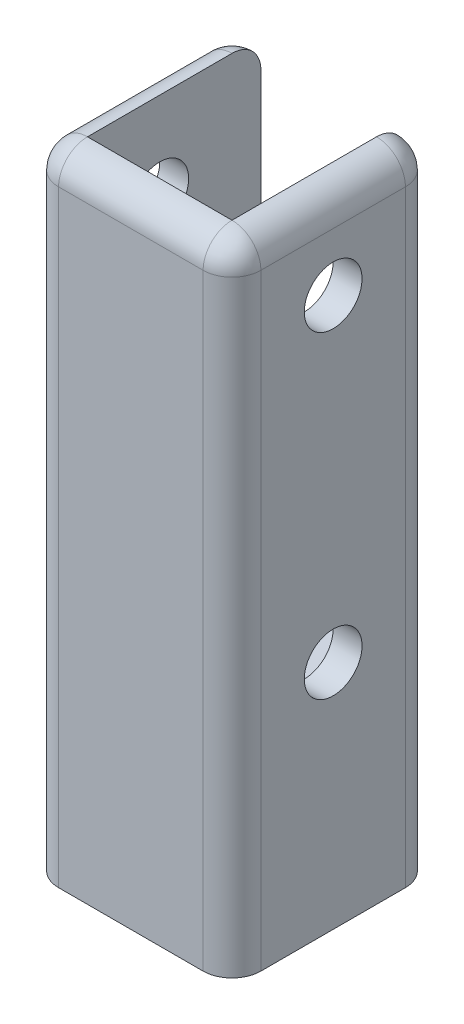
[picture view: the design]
ISO-10303-21;
HEADER;
FILE_DESCRIPTION(('STEP AP214'),'2;1');
FILE_NAME('part.step','',(''),(''),'','','');
FILE_SCHEMA(('AUTOMOTIVE_DESIGN { 1 0 10303 214 1 1 1 1 }'));
ENDSEC;
DATA;
#1=APPLICATION_CONTEXT('core data for automotive mechanical design processes');
#2=APPLICATION_PROTOCOL_DEFINITION('international standard','automotive_design',2000,#1);
#3=PRODUCT_CONTEXT('',#1,'mechanical');
#4=PRODUCT('Part','Part','',(#3));
#5=PRODUCT_RELATED_PRODUCT_CATEGORY('part','',(#4));
#6=PRODUCT_DEFINITION_FORMATION('','',#4);
#7=PRODUCT_DEFINITION_CONTEXT('part definition',#1,'design');
#8=PRODUCT_DEFINITION('design','',#6,#7);
#9=PRODUCT_DEFINITION_SHAPE('','',#8);
#10=(LENGTH_UNIT() NAMED_UNIT(*) SI_UNIT(.MILLI.,.METRE.));
#11=(NAMED_UNIT(*) PLANE_ANGLE_UNIT() SI_UNIT($,.RADIAN.));
#12=(NAMED_UNIT(*) SI_UNIT($,.STERADIAN.) SOLID_ANGLE_UNIT());
#13=UNCERTAINTY_MEASURE_WITH_UNIT(LENGTH_MEASURE(1.E-05),#10,'distance_accuracy_value','');
#14=(GEOMETRIC_REPRESENTATION_CONTEXT(3) GLOBAL_UNCERTAINTY_ASSIGNED_CONTEXT((#13)) GLOBAL_UNIT_ASSIGNED_CONTEXT((#10,
#11,#12)) REPRESENTATION_CONTEXT('',''));
#15=CARTESIAN_POINT('',(0.,0.,0.));
#16=DIRECTION('',(0.,0.,1.));
#17=DIRECTION('',(1.,0.,0.));
#18=AXIS2_PLACEMENT_3D('',#15,#16,#17);
#19=CARTESIAN_POINT('',(0.,55.,0.));
#20=DIRECTION('',(0.,1.,0.));
#21=DIRECTION('',(0.,0.,1.));
#22=AXIS2_PLACEMENT_3D('',#19,#20,#21);
#23=PLANE('',#22);
#24=DIRECTION('',(1.,0.,0.));
#25=VECTOR('',#24,1.);
#26=CARTESIAN_POINT('',(0.,55.,25.));
#27=LINE('',#26,#25);
#28=CARTESIAN_POINT('',(-25.,55.,25.0000000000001));
#29=VERTEX_POINT('',#28);
#30=CARTESIAN_POINT('',(25.,55.,25.));
#31=VERTEX_POINT('',#30);
#32=EDGE_CURVE('E278',#29,#31,#27,.T.);
#33=ORIENTED_EDGE('',*,*,#32,.T.);
#34=DIRECTION('',(0.,0.,-1.));
#35=VECTOR('',#34,1.);
#36=CARTESIAN_POINT('',(25.,55.,0.));
#37=LINE('',#36,#35);
#38=CARTESIAN_POINT('',(25.,55.,-35.));
#39=VERTEX_POINT('',#38);
#40=EDGE_CURVE('E264',#31,#39,#37,.T.);
#41=ORIENTED_EDGE('',*,*,#40,.T.);
#42=DIRECTION('',(-1.,0.,0.));
#43=VECTOR('',#42,1.);
#44=CARTESIAN_POINT('',(0.,55.,-35.));
#45=LINE('',#44,#43);
#46=CARTESIAN_POINT('',(-25.,55.,-35.));
#47=VERTEX_POINT('',#46);
#48=EDGE_CURVE('E266',#39,#47,#45,.T.);
#49=ORIENTED_EDGE('',*,*,#48,.T.);
#50=DIRECTION('',(0.,0.,1.));
#51=VECTOR('',#50,1.);
#52=CARTESIAN_POINT('',(-25.,55.,0.));
#53=LINE('',#52,#51);
#54=EDGE_CURVE('E259',#47,#29,#53,.T.);
#55=ORIENTED_EDGE('',*,*,#54,.T.);
#56=EDGE_LOOP('',(#33,#41,#49,#55));
#57=FACE_BOUND('',#56,.T.);
#58=ADVANCED_FACE('F41',(#57),#23,.T.);
#59=CARTESIAN_POINT('',(25.,0.,25.));
#60=DIRECTION('',(0.,1.,0.));
#61=DIRECTION('',(0.,0.,1.));
#62=AXIS2_PLACEMENT_3D('',#59,#60,#61);
#63=PLANE('',#62);
#64=CARTESIAN_POINT('',(-24.0588806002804,0.,-23.6603413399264));
#65=DIRECTION('',(0.,-1.,0.));
#66=DIRECTION('',(0.,0.,-1.));
#67=AXIS2_PLACEMENT_3D('',#64,#65,#66);
#68=CIRCLE('',#67,2.5);
#69=CARTESIAN_POINT('',(-24.0588806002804,0.,-26.1603413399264));
#70=VERTEX_POINT('',#69);
#71=EDGE_CURVE('E489',#70,#70,#68,.T.);
#72=ORIENTED_EDGE('',*,*,#71,.F.);
#73=EDGE_LOOP('',(#72));
#74=FACE_BOUND('',#73,.T.);
#75=CARTESIAN_POINT('',(22.9411193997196,0.,-23.6603413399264));
#76=DIRECTION('',(0.,-1.,0.));
#77=DIRECTION('',(0.,0.,-1.));
#78=AXIS2_PLACEMENT_3D('',#75,#76,#77);
#79=CIRCLE('',#78,2.5);
#80=CARTESIAN_POINT('',(22.9411193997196,0.,-26.1603413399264));
#81=VERTEX_POINT('',#80);
#82=EDGE_CURVE('E1132',#81,#81,#79,.T.);
#83=ORIENTED_EDGE('',*,*,#82,.F.);
#84=EDGE_LOOP('',(#83));
#85=FACE_BOUND('',#84,.T.);
#86=CARTESIAN_POINT('',(22.9411193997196,0.,23.3396586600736));
#87=DIRECTION('',(0.,-1.,0.));
#88=DIRECTION('',(0.,0.,-1.));
#89=AXIS2_PLACEMENT_3D('',#86,#87,#88);
#90=CIRCLE('',#89,2.5);
#91=CARTESIAN_POINT('',(22.9411193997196,0.,20.8396586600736));
#92=VERTEX_POINT('',#91);
#93=EDGE_CURVE('E506',#92,#92,#90,.T.);
#94=ORIENTED_EDGE('',*,*,#93,.F.);
#95=EDGE_LOOP('',(#94));
#96=FACE_BOUND('',#95,.T.);
#97=CARTESIAN_POINT('',(-24.0588806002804,0.,23.3396586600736));
#98=DIRECTION('',(0.,-1.,0.));
#99=DIRECTION('',(0.,0.,-1.));
#100=AXIS2_PLACEMENT_3D('',#97,#98,#99);
#101=CIRCLE('',#100,2.5);
#102=CARTESIAN_POINT('',(-24.0588806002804,0.,20.8396586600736));
#103=VERTEX_POINT('',#102);
#104=EDGE_CURVE('E503',#103,#103,#101,.T.);
#105=ORIENTED_EDGE('',*,*,#104,.F.);
#106=EDGE_LOOP('',(#105));
#107=FACE_BOUND('',#106,.T.);
#108=CARTESIAN_POINT('',(25.,0.,25.));
#109=DIRECTION('',(0.,1.,0.));
#110=DIRECTION('',(0.,0.,1.));
#111=AXIS2_PLACEMENT_3D('',#108,#109,#110);
#112=CIRCLE('',#111,10.);
#113=CARTESIAN_POINT('',(25.,0.,35.));
#114=VERTEX_POINT('',#113);
#115=CARTESIAN_POINT('',(35.,0.,25.));
#116=VERTEX_POINT('',#115);
#117=EDGE_CURVE('E420',#114,#116,#112,.T.);
#118=ORIENTED_EDGE('',*,*,#117,.F.);
#119=DIRECTION('',(1.,0.,0.));
#120=VECTOR('',#119,1.);
#121=CARTESIAN_POINT('',(-25.,0.,35.));
#122=LINE('',#121,#120);
#123=CARTESIAN_POINT('',(-25.,0.,35.));
#124=VERTEX_POINT('',#123);
#125=EDGE_CURVE('E437',#124,#114,#122,.T.);
#126=ORIENTED_EDGE('',*,*,#125,.F.);
#127=CARTESIAN_POINT('',(-25.,0.,25.));
#128=DIRECTION('',(0.,1.,0.));
#129=DIRECTION('',(0.,0.,-1.));
#130=AXIS2_PLACEMENT_3D('',#127,#128,#129);
#131=CIRCLE('',#130,10.);
#132=CARTESIAN_POINT('',(-35.,0.,25.));
#133=VERTEX_POINT('',#132);
#134=EDGE_CURVE('E436',#133,#124,#131,.T.);
#135=ORIENTED_EDGE('',*,*,#134,.F.);
#136=DIRECTION('',(0.,0.,1.));
#137=VECTOR('',#136,1.);
#138=CARTESIAN_POINT('',(-35.,0.,-25.));
#139=LINE('',#138,#137);
#140=CARTESIAN_POINT('',(-35.,0.,-25.));
#141=VERTEX_POINT('',#140);
#142=EDGE_CURVE('E433',#141,#133,#139,.T.);
#143=ORIENTED_EDGE('',*,*,#142,.F.);
#144=CARTESIAN_POINT('',(-25.,0.,-25.));
#145=DIRECTION('',(0.,1.,0.));
#146=DIRECTION('',(0.,0.,1.));
#147=AXIS2_PLACEMENT_3D('',#144,#145,#146);
#148=CIRCLE('',#147,9.99999999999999);
#149=CARTESIAN_POINT('',(-25.,0.,-35.));
#150=VERTEX_POINT('',#149);
#151=EDGE_CURVE('E427',#150,#141,#148,.T.);
#152=ORIENTED_EDGE('',*,*,#151,.F.);
#153=DIRECTION('',(-1.,0.,0.));
#154=VECTOR('',#153,1.);
#155=CARTESIAN_POINT('',(-25.,0.,-35.));
#156=LINE('',#155,#154);
#157=CARTESIAN_POINT('',(25.,0.,-35.));
#158=VERTEX_POINT('',#157);
#159=EDGE_CURVE('E426',#158,#150,#156,.T.);
#160=ORIENTED_EDGE('',*,*,#159,.F.);
#161=CARTESIAN_POINT('',(25.,0.,-25.));
#162=DIRECTION('',(0.,1.,0.));
#163=DIRECTION('',(0.,0.,1.));
#164=AXIS2_PLACEMENT_3D('',#161,#162,#163);
#165=CIRCLE('',#164,10.);
#166=CARTESIAN_POINT('',(35.,0.,-25.));
#167=VERTEX_POINT('',#166);
#168=EDGE_CURVE('E428',#167,#158,#165,.T.);
#169=ORIENTED_EDGE('',*,*,#168,.F.);
#170=DIRECTION('',(0.,0.,-1.));
#171=VECTOR('',#170,1.);
#172=CARTESIAN_POINT('',(35.,0.,-25.));
#173=LINE('',#172,#171);
#174=EDGE_CURVE('E421',#116,#167,#173,.T.);
#175=ORIENTED_EDGE('',*,*,#174,.F.);
#176=EDGE_LOOP('',(#118,#126,#135,#143,#152,#160,#169,#175));
#177=FACE_BOUND('',#176,.T.);
#178=CARTESIAN_POINT('',(-16.2788154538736,0.,25.2996586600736));
#179=DIRECTION('',(0.,1.,0.));
#180=DIRECTION('',(0.,0.,1.));
#181=AXIS2_PLACEMENT_3D('',#178,#179,#180);
#182=CIRCLE('',#181,2.53999999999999);
#183=CARTESIAN_POINT('',(-18.7661651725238,0.,25.8141403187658));
#184=VERTEX_POINT('',#183);
#185=CARTESIAN_POINT('',(-16.2788154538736,0.,27.8396586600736));
#186=VERTEX_POINT('',#185);
#187=EDGE_CURVE('E290',#184,#186,#182,.T.);
#188=ORIENTED_EDGE('',*,*,#187,.T.);
#189=DIRECTION('',(1.,0.,0.));
#190=VECTOR('',#189,1.);
#191=CARTESIAN_POINT('',(-16.2788154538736,0.,27.8396586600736));
#192=LINE('',#191,#190);
#193=CARTESIAN_POINT('',(15.1610542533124,0.,27.8396586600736));
#194=VERTEX_POINT('',#193);
#195=EDGE_CURVE('E345',#186,#194,#192,.T.);
#196=ORIENTED_EDGE('',*,*,#195,.T.);
#197=CARTESIAN_POINT('',(15.1610542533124,0.,25.2996586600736));
#198=DIRECTION('',(0.,1.,0.));
#199=DIRECTION('',(0.,0.,1.));
#200=AXIS2_PLACEMENT_3D('',#197,#198,#199);
#201=CIRCLE('',#200,2.53999999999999);
#202=CARTESIAN_POINT('',(17.6484039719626,0.,25.8141403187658));
#203=VERTEX_POINT('',#202);
#204=EDGE_CURVE('E348',#194,#203,#201,.T.);
#205=ORIENTED_EDGE('',*,*,#204,.T.);
#206=CARTESIAN_POINT('',(27.4411193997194,0.,27.8396586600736));
#207=DIRECTION('',(0.,-1.,0.));
#208=DIRECTION('',(0.,0.,1.));
#209=AXIS2_PLACEMENT_3D('',#206,#207,#208);
#210=CIRCLE('',#209,10.);
#211=CARTESIAN_POINT('',(25.4156010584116,0.,18.0469432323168));
#212=VERTEX_POINT('',#211);
#213=EDGE_CURVE('E350',#203,#212,#210,.T.);
#214=ORIENTED_EDGE('',*,*,#213,.T.);
#215=CARTESIAN_POINT('',(24.9011193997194,0.,15.5595935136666));
#216=DIRECTION('',(0.,1.,0.));
#217=DIRECTION('',(0.,0.,1.));
#218=AXIS2_PLACEMENT_3D('',#215,#216,#217);
#219=CIRCLE('',#218,2.53999999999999);
#220=CARTESIAN_POINT('',(27.4411193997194,0.,15.5595935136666));
#221=VERTEX_POINT('',#220);
#222=EDGE_CURVE('E352',#212,#221,#219,.T.);
#223=ORIENTED_EDGE('',*,*,#222,.T.);
#224=DIRECTION('',(0.,0.,-1.));
#225=VECTOR('',#224,1.);
#226=CARTESIAN_POINT('',(27.4411193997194,0.,15.5595935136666));
#227=LINE('',#226,#225);
#228=CARTESIAN_POINT('',(27.4411193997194,0.,-15.8802761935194));
#229=VERTEX_POINT('',#228);
#230=EDGE_CURVE('E355',#221,#229,#227,.T.);
#231=ORIENTED_EDGE('',*,*,#230,.T.);
#232=CARTESIAN_POINT('',(24.9011193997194,0.,-15.8802761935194));
#233=DIRECTION('',(0.,1.,0.));
#234=DIRECTION('',(0.,0.,1.));
#235=AXIS2_PLACEMENT_3D('',#232,#233,#234);
#236=CIRCLE('',#235,2.53999999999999);
#237=CARTESIAN_POINT('',(25.4156010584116,0.,-18.3676259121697));
#238=VERTEX_POINT('',#237);
#239=EDGE_CURVE('E356',#229,#238,#236,.T.);
#240=ORIENTED_EDGE('',*,*,#239,.T.);
#241=CARTESIAN_POINT('',(27.4411193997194,0.,-28.1603413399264));
#242=DIRECTION('',(0.,-1.,0.));
#243=DIRECTION('',(0.,0.,1.));
#244=AXIS2_PLACEMENT_3D('',#241,#242,#243);
#245=CIRCLE('',#244,10.);
#246=CARTESIAN_POINT('',(17.6484039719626,0.,-26.1348229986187));
#247=VERTEX_POINT('',#246);
#248=EDGE_CURVE('E363',#238,#247,#245,.T.);
#249=ORIENTED_EDGE('',*,*,#248,.T.);
#250=CARTESIAN_POINT('',(15.1610542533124,0.,-25.6203413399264));
#251=DIRECTION('',(0.,1.,0.));
#252=DIRECTION('',(0.,0.,1.));
#253=AXIS2_PLACEMENT_3D('',#250,#251,#252);
#254=CIRCLE('',#253,2.53999999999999);
#255=CARTESIAN_POINT('',(15.1610542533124,0.,-28.1603413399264));
#256=VERTEX_POINT('',#255);
#257=EDGE_CURVE('E364',#247,#256,#254,.T.);
#258=ORIENTED_EDGE('',*,*,#257,.T.);
#259=DIRECTION('',(-1.,0.,0.));
#260=VECTOR('',#259,1.);
#261=CARTESIAN_POINT('',(15.1610542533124,0.,-28.1603413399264));
#262=LINE('',#261,#260);
#263=CARTESIAN_POINT('',(-16.2788154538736,0.,-28.1603413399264));
#264=VERTEX_POINT('',#263);
#265=EDGE_CURVE('E370',#256,#264,#262,.T.);
#266=ORIENTED_EDGE('',*,*,#265,.T.);
#267=CARTESIAN_POINT('',(-16.2788154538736,0.,-25.6203413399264));
#268=DIRECTION('',(0.,1.,0.));
#269=DIRECTION('',(0.,0.,1.));
#270=AXIS2_PLACEMENT_3D('',#267,#268,#269);
#271=CIRCLE('',#270,2.53999999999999);
#272=CARTESIAN_POINT('',(-18.7661651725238,0.,-26.1348229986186));
#273=VERTEX_POINT('',#272);
#274=EDGE_CURVE('E369',#264,#273,#271,.T.);
#275=ORIENTED_EDGE('',*,*,#274,.T.);
#276=CARTESIAN_POINT('',(-28.5588806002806,0.,-28.1603413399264));
#277=DIRECTION('',(0.,-1.,0.));
#278=DIRECTION('',(0.,0.,1.));
#279=AXIS2_PLACEMENT_3D('',#276,#277,#278);
#280=CIRCLE('',#279,10.);
#281=CARTESIAN_POINT('',(-26.5333622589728,0.,-18.3676259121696));
#282=VERTEX_POINT('',#281);
#283=EDGE_CURVE('E373',#273,#282,#280,.T.);
#284=ORIENTED_EDGE('',*,*,#283,.T.);
#285=CARTESIAN_POINT('',(-26.0188806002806,0.,-15.8802761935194));
#286=DIRECTION('',(0.,1.,0.));
#287=DIRECTION('',(0.,0.,1.));
#288=AXIS2_PLACEMENT_3D('',#285,#286,#287);
#289=CIRCLE('',#288,2.53999999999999);
#290=CARTESIAN_POINT('',(-28.5588806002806,0.,-15.8802761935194));
#291=VERTEX_POINT('',#290);
#292=EDGE_CURVE('E376',#282,#291,#289,.T.);
#293=ORIENTED_EDGE('',*,*,#292,.T.);
#294=DIRECTION('',(0.,0.,1.));
#295=VECTOR('',#294,1.);
#296=CARTESIAN_POINT('',(-28.5588806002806,0.,-15.8802761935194));
#297=LINE('',#296,#295);
#298=CARTESIAN_POINT('',(-28.5588806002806,0.,15.5595935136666));
#299=VERTEX_POINT('',#298);
#300=EDGE_CURVE('E378',#291,#299,#297,.T.);
#301=ORIENTED_EDGE('',*,*,#300,.T.);
#302=CARTESIAN_POINT('',(-26.0188806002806,0.,15.5595935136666));
#303=DIRECTION('',(0.,1.,0.));
#304=DIRECTION('',(0.,0.,1.));
#305=AXIS2_PLACEMENT_3D('',#302,#303,#304);
#306=CIRCLE('',#305,2.53999999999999);
#307=CARTESIAN_POINT('',(-26.5333622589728,0.,18.0469432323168));
#308=VERTEX_POINT('',#307);
#309=EDGE_CURVE('E385',#299,#308,#306,.T.);
#310=ORIENTED_EDGE('',*,*,#309,.T.);
#311=CARTESIAN_POINT('',(-28.5588806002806,0.,27.8396586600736));
#312=DIRECTION('',(0.,-1.,0.));
#313=DIRECTION('',(0.,0.,1.));
#314=AXIS2_PLACEMENT_3D('',#311,#312,#313);
#315=CIRCLE('',#314,10.);
#316=EDGE_CURVE('E294',#308,#184,#315,.T.);
#317=ORIENTED_EDGE('',*,*,#316,.T.);
#318=EDGE_LOOP('',(#188,#196,#205,#214,#223,#231,#240,#249,#258,#266,#275,#284,#293,#301,#310,#317));
#319=FACE_BOUND('',#318,.T.);
#320=ADVANCED_FACE('F542',(#74,#85,#96,#107,#177,#319),#63,.F.);
#321=CARTESIAN_POINT('',(25.,50.,25.));
#322=DIRECTION('',(0.,-1.,0.));
#323=DIRECTION('',(0.,0.,-1.));
#324=AXIS2_PLACEMENT_3D('',#321,#322,#323);
#325=CYLINDRICAL_SURFACE('',#324,10.);
#326=DIRECTION('',(0.,-1.,0.));
#327=VECTOR('',#326,1.);
#328=CARTESIAN_POINT('',(35.,50.,25.));
#329=LINE('',#328,#327);
#330=CARTESIAN_POINT('',(35.,210.,25.));
#331=VERTEX_POINT('',#330);
#332=EDGE_CURVE('E457',#331,#116,#329,.T.);
#333=ORIENTED_EDGE('',*,*,#332,.F.);
#334=CARTESIAN_POINT('',(25.,210.,25.));
#335=DIRECTION('',(0.,-1.,0.));
#336=DIRECTION('',(0.,0.,-1.));
#337=AXIS2_PLACEMENT_3D('',#334,#335,#336);
#338=CIRCLE('',#337,10.);
#339=CARTESIAN_POINT('',(25.,210.,35.));
#340=VERTEX_POINT('',#339);
#341=EDGE_CURVE('E243',#331,#340,#338,.T.);
#342=ORIENTED_EDGE('',*,*,#341,.T.);
#343=DIRECTION('',(0.,-1.,0.));
#344=VECTOR('',#343,1.);
#345=CARTESIAN_POINT('',(25.,50.,35.));
#346=LINE('',#345,#344);
#347=EDGE_CURVE('E445',#340,#114,#346,.T.);
#348=ORIENTED_EDGE('',*,*,#347,.T.);
#349=ORIENTED_EDGE('',*,*,#117,.T.);
#350=EDGE_LOOP('',(#333,#342,#348,#349));
#351=FACE_BOUND('',#350,.T.);
#352=ADVANCED_FACE('F550',(#351),#325,.T.);
#353=CARTESIAN_POINT('',(35.,50.,-25.));
#354=DIRECTION('',(-1.,0.,0.));
#355=DIRECTION('',(0.,0.,1.));
#356=AXIS2_PLACEMENT_3D('',#353,#354,#355);
#357=PLANE('',#356);
#358=CARTESIAN_POINT('',(35.,80.,0.));
#359=DIRECTION('',(-1.,0.,0.));
#360=DIRECTION('',(0.,0.,1.));
#361=AXIS2_PLACEMENT_3D('',#358,#359,#360);
#362=CIRCLE('',#361,10.);
#363=CARTESIAN_POINT('',(35.,80.,10.));
#364=VERTEX_POINT('',#363);
#365=EDGE_CURVE('E277',#364,#364,#362,.T.);
#366=ORIENTED_EDGE('',*,*,#365,.T.);
#367=EDGE_LOOP('',(#366));
#368=FACE_BOUND('',#367,.T.);
#369=CARTESIAN_POINT('',(35.,190.,0.));
#370=DIRECTION('',(-1.,0.,0.));
#371=DIRECTION('',(0.,0.,1.));
#372=AXIS2_PLACEMENT_3D('',#369,#370,#371);
#373=CIRCLE('',#372,10.);
#374=CARTESIAN_POINT('',(35.,190.,10.));
#375=VERTEX_POINT('',#374);
#376=EDGE_CURVE('E469',#375,#375,#373,.T.);
#377=ORIENTED_EDGE('',*,*,#376,.T.);
#378=EDGE_LOOP('',(#377));
#379=FACE_BOUND('',#378,.T.);
#380=DIRECTION('',(0.,-1.,0.));
#381=VECTOR('',#380,1.);
#382=CARTESIAN_POINT('',(35.,50.,-25.));
#383=LINE('',#382,#381);
#384=CARTESIAN_POINT('',(35.,210.,-25.));
#385=VERTEX_POINT('',#384);
#386=EDGE_CURVE('E458',#385,#167,#383,.T.);
#387=ORIENTED_EDGE('',*,*,#386,.F.);
#388=DIRECTION('',(0.,0.,-1.));
#389=VECTOR('',#388,1.);
#390=CARTESIAN_POINT('',(35.,210.,25.));
#391=LINE('',#390,#389);
#392=EDGE_CURVE('E479',#385,#331,#391,.F.);
#393=ORIENTED_EDGE('',*,*,#392,.T.);
#394=ORIENTED_EDGE('',*,*,#332,.T.);
#395=ORIENTED_EDGE('',*,*,#174,.T.);
#396=EDGE_LOOP('',(#387,#393,#394,#395));
#397=FACE_BOUND('',#396,.T.);
#398=ADVANCED_FACE('F518',(#368,#379,#397),#357,.F.);
#399=CARTESIAN_POINT('',(25.,50.,-25.));
#400=DIRECTION('',(0.,-1.,0.));
#401=DIRECTION('',(0.,0.,-1.));
#402=AXIS2_PLACEMENT_3D('',#399,#400,#401);
#403=CYLINDRICAL_SURFACE('',#402,10.);
#404=DIRECTION('',(0.,-1.,0.));
#405=VECTOR('',#404,1.);
#406=CARTESIAN_POINT('',(25.,220.,-35.));
#407=LINE('',#406,#405);
#408=CARTESIAN_POINT('',(25.,210.,-35.));
#409=VERTEX_POINT('',#408);
#410=EDGE_CURVE('E274',#409,#39,#407,.T.);
#411=ORIENTED_EDGE('',*,*,#410,.F.);
#412=CARTESIAN_POINT('',(25.,210.,-25.));
#413=DIRECTION('',(0.,-1.,0.));
#414=DIRECTION('',(0.,0.,-1.));
#415=AXIS2_PLACEMENT_3D('',#412,#413,#414);
#416=CIRCLE('',#415,10.);
#417=EDGE_CURVE('E472',#409,#385,#416,.T.);
#418=ORIENTED_EDGE('',*,*,#417,.T.);
#419=ORIENTED_EDGE('',*,*,#386,.T.);
#420=ORIENTED_EDGE('',*,*,#168,.T.);
#421=DIRECTION('',(0.,-1.,0.));
#422=VECTOR('',#421,1.);
#423=CARTESIAN_POINT('',(25.,50.,-35.));
#424=LINE('',#423,#422);
#425=EDGE_CURVE('E455',#39,#158,#424,.T.);
#426=ORIENTED_EDGE('',*,*,#425,.F.);
#427=EDGE_LOOP('',(#411,#418,#419,#420,#426));
#428=FACE_BOUND('',#427,.T.);
#429=ADVANCED_FACE('F639',(#428),#403,.T.);
#430=CARTESIAN_POINT('',(-25.,50.,-35.));
#431=DIRECTION('',(0.,0.,1.));
#432=DIRECTION('',(1.,0.,0.));
#433=AXIS2_PLACEMENT_3D('',#430,#431,#432);
#434=PLANE('',#433);
#435=ORIENTED_EDGE('',*,*,#159,.T.);
#436=DIRECTION('',(0.,-1.,0.));
#437=VECTOR('',#436,1.);
#438=CARTESIAN_POINT('',(-25.,50.,-35.));
#439=LINE('',#438,#437);
#440=EDGE_CURVE('E448',#47,#150,#439,.T.);
#441=ORIENTED_EDGE('',*,*,#440,.F.);
#442=ORIENTED_EDGE('',*,*,#48,.F.);
#443=ORIENTED_EDGE('',*,*,#425,.T.);
#444=EDGE_LOOP('',(#435,#441,#442,#443));
#445=FACE_BOUND('',#444,.T.);
#446=ADVANCED_FACE('F637',(#445),#434,.F.);
#447=CARTESIAN_POINT('',(-25.,50.,-25.));
#448=DIRECTION('',(0.,-1.,0.));
#449=DIRECTION('',(0.,0.,-1.));
#450=AXIS2_PLACEMENT_3D('',#447,#448,#449);
#451=CYLINDRICAL_SURFACE('',#450,9.99999999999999);
#452=DIRECTION('',(0.,-1.,0.));
#453=VECTOR('',#452,1.);
#454=CARTESIAN_POINT('',(-35.,50.,-25.));
#455=LINE('',#454,#453);
#456=CARTESIAN_POINT('',(-35.,210.,-25.));
#457=VERTEX_POINT('',#456);
#458=EDGE_CURVE('E449',#457,#141,#455,.T.);
#459=ORIENTED_EDGE('',*,*,#458,.F.);
#460=CARTESIAN_POINT('',(-25.,210.,-25.));
#461=DIRECTION('',(0.,-1.,0.));
#462=DIRECTION('',(0.,0.,-1.));
#463=AXIS2_PLACEMENT_3D('',#460,#461,#462);
#464=CIRCLE('',#463,9.99999999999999);
#465=CARTESIAN_POINT('',(-25.,210.,-35.));
#466=VERTEX_POINT('',#465);
#467=EDGE_CURVE('E59',#457,#466,#464,.T.);
#468=ORIENTED_EDGE('',*,*,#467,.T.);
#469=DIRECTION('',(0.,-1.,0.));
#470=VECTOR('',#469,1.);
#471=CARTESIAN_POINT('',(-25.,220.,-35.));
#472=LINE('',#471,#470);
#473=EDGE_CURVE('E281',#466,#47,#472,.T.);
#474=ORIENTED_EDGE('',*,*,#473,.T.);
#475=ORIENTED_EDGE('',*,*,#440,.T.);
#476=ORIENTED_EDGE('',*,*,#151,.T.);
#477=EDGE_LOOP('',(#459,#468,#474,#475,#476));
#478=FACE_BOUND('',#477,.T.);
#479=ADVANCED_FACE('F632',(#478),#451,.T.);
#480=CARTESIAN_POINT('',(-35.,50.,-25.));
#481=DIRECTION('',(1.,0.,0.));
#482=DIRECTION('',(0.,0.,-1.));
#483=AXIS2_PLACEMENT_3D('',#480,#481,#482);
#484=PLANE('',#483);
#485=CARTESIAN_POINT('',(-35.,80.,0.));
#486=DIRECTION('',(-1.,0.,0.));
#487=DIRECTION('',(0.,0.,1.));
#488=AXIS2_PLACEMENT_3D('',#485,#486,#487);
#489=CIRCLE('',#488,10.);
#490=CARTESIAN_POINT('',(-35.,80.,10.));
#491=VERTEX_POINT('',#490);
#492=EDGE_CURVE('E463',#491,#491,#489,.T.);
#493=ORIENTED_EDGE('',*,*,#492,.F.);
#494=EDGE_LOOP('',(#493));
#495=FACE_BOUND('',#494,.T.);
#496=CARTESIAN_POINT('',(-35.,190.,0.));
#497=DIRECTION('',(-1.,0.,0.));
#498=DIRECTION('',(0.,0.,1.));
#499=AXIS2_PLACEMENT_3D('',#496,#497,#498);
#500=CIRCLE('',#499,10.);
#501=CARTESIAN_POINT('',(-35.,190.,10.));
#502=VERTEX_POINT('',#501);
#503=EDGE_CURVE('E505',#502,#502,#500,.T.);
#504=ORIENTED_EDGE('',*,*,#503,.F.);
#505=EDGE_LOOP('',(#504));
#506=FACE_BOUND('',#505,.T.);
#507=DIRECTION('',(0.,-1.,0.));
#508=VECTOR('',#507,1.);
#509=CARTESIAN_POINT('',(-35.,50.,25.));
#510=LINE('',#509,#508);
#511=CARTESIAN_POINT('',(-35.,210.,25.));
#512=VERTEX_POINT('',#511);
#513=EDGE_CURVE('E447',#512,#133,#510,.T.);
#514=ORIENTED_EDGE('',*,*,#513,.F.);
#515=DIRECTION('',(0.,0.,1.));
#516=VECTOR('',#515,1.);
#517=CARTESIAN_POINT('',(-35.,210.,-25.));
#518=LINE('',#517,#516);
#519=EDGE_CURVE('E11',#512,#457,#518,.F.);
#520=ORIENTED_EDGE('',*,*,#519,.T.);
#521=ORIENTED_EDGE('',*,*,#458,.T.);
#522=ORIENTED_EDGE('',*,*,#142,.T.);
#523=EDGE_LOOP('',(#514,#520,#521,#522));
#524=FACE_BOUND('',#523,.T.);
#525=ADVANCED_FACE('F629',(#495,#506,#524),#484,.F.);
#526=CARTESIAN_POINT('',(-25.,50.,25.));
#527=DIRECTION('',(0.,-1.,0.));
#528=DIRECTION('',(0.,0.,-1.));
#529=AXIS2_PLACEMENT_3D('',#526,#527,#528);
#530=CYLINDRICAL_SURFACE('',#529,10.);
#531=DIRECTION('',(0.,-1.,0.));
#532=VECTOR('',#531,1.);
#533=CARTESIAN_POINT('',(-25.,50.,35.));
#534=LINE('',#533,#532);
#535=CARTESIAN_POINT('',(-25.,210.,35.));
#536=VERTEX_POINT('',#535);
#537=EDGE_CURVE('E443',#536,#124,#534,.T.);
#538=ORIENTED_EDGE('',*,*,#537,.F.);
#539=CARTESIAN_POINT('',(-25.,210.,25.));
#540=DIRECTION('',(0.,-1.,0.));
#541=DIRECTION('',(0.,0.,-1.));
#542=AXIS2_PLACEMENT_3D('',#539,#540,#541);
#543=CIRCLE('',#542,10.);
#544=EDGE_CURVE('E474',#536,#512,#543,.T.);
#545=ORIENTED_EDGE('',*,*,#544,.T.);
#546=ORIENTED_EDGE('',*,*,#513,.T.);
#547=ORIENTED_EDGE('',*,*,#134,.T.);
#548=EDGE_LOOP('',(#538,#545,#546,#547));
#549=FACE_BOUND('',#548,.T.);
#550=ADVANCED_FACE('F626',(#549),#530,.T.);
#551=CARTESIAN_POINT('',(-25.,50.,35.));
#552=DIRECTION('',(0.,0.,-1.));
#553=DIRECTION('',(-1.,0.,0.));
#554=AXIS2_PLACEMENT_3D('',#551,#552,#553);
#555=PLANE('',#554);
#556=ORIENTED_EDGE('',*,*,#347,.F.);
#557=DIRECTION('',(1.,0.,0.));
#558=VECTOR('',#557,1.);
#559=CARTESIAN_POINT('',(-25.,210.,35.));
#560=LINE('',#559,#558);
#561=EDGE_CURVE('E234',#340,#536,#560,.F.);
#562=ORIENTED_EDGE('',*,*,#561,.T.);
#563=ORIENTED_EDGE('',*,*,#537,.T.);
#564=ORIENTED_EDGE('',*,*,#125,.T.);
#565=EDGE_LOOP('',(#556,#562,#563,#564));
#566=FACE_BOUND('',#565,.T.);
#567=ADVANCED_FACE('F623',(#566),#555,.F.);
#568=CARTESIAN_POINT('',(-16.2788154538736,50.,25.2996586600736));
#569=DIRECTION('',(0.,-1.,0.));
#570=DIRECTION('',(0.,0.,-1.));
#571=AXIS2_PLACEMENT_3D('',#568,#569,#570);
#572=CYLINDRICAL_SURFACE('',#571,2.53999999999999);
#573=ORIENTED_EDGE('',*,*,#187,.F.);
#574=DIRECTION('',(0.,-1.,0.));
#575=VECTOR('',#574,1.);
#576=CARTESIAN_POINT('',(-18.7661651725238,50.,25.8141403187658));
#577=LINE('',#576,#575);
#578=CARTESIAN_POINT('',(-18.7661651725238,50.,25.8141403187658));
#579=VERTEX_POINT('',#578);
#580=EDGE_CURVE('E338',#579,#184,#577,.T.);
#581=ORIENTED_EDGE('',*,*,#580,.F.);
#582=CARTESIAN_POINT('',(-16.2788154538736,50.,25.2996586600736));
#583=DIRECTION('',(0.,1.,0.));
#584=DIRECTION('',(0.,0.,1.));
#585=AXIS2_PLACEMENT_3D('',#582,#583,#584);
#586=CIRCLE('',#585,2.53999999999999);
#587=CARTESIAN_POINT('',(-16.2788154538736,50.,27.8396586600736));
#588=VERTEX_POINT('',#587);
#589=EDGE_CURVE('E293',#579,#588,#586,.T.);
#590=ORIENTED_EDGE('',*,*,#589,.T.);
#591=DIRECTION('',(0.,-1.,0.));
#592=VECTOR('',#591,1.);
#593=CARTESIAN_POINT('',(-16.2788154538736,50.,27.8396586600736));
#594=LINE('',#593,#592);
#595=EDGE_CURVE('E417',#588,#186,#594,.T.);
#596=ORIENTED_EDGE('',*,*,#595,.T.);
#597=EDGE_LOOP('',(#573,#581,#590,#596));
#598=FACE_BOUND('',#597,.T.);
#599=ADVANCED_FACE('F616',(#598),#572,.F.);
#600=CARTESIAN_POINT('',(-16.2788154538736,50.,27.8396586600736));
#601=DIRECTION('',(0.,0.,-1.));
#602=DIRECTION('',(-1.,0.,0.));
#603=AXIS2_PLACEMENT_3D('',#600,#601,#602);
#604=PLANE('',#603);
#605=ORIENTED_EDGE('',*,*,#195,.F.);
#606=ORIENTED_EDGE('',*,*,#595,.F.);
#607=DIRECTION('',(1.,0.,0.));
#608=VECTOR('',#607,1.);
#609=CARTESIAN_POINT('',(-16.2788154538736,50.,27.8396586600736));
#610=LINE('',#609,#608);
#611=CARTESIAN_POINT('',(15.1610542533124,50.,27.8396586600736));
#612=VERTEX_POINT('',#611);
#613=EDGE_CURVE('E295',#588,#612,#610,.T.);
#614=ORIENTED_EDGE('',*,*,#613,.T.);
#615=DIRECTION('',(0.,-1.,0.));
#616=VECTOR('',#615,1.);
#617=CARTESIAN_POINT('',(15.1610542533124,50.,27.8396586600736));
#618=LINE('',#617,#616);
#619=EDGE_CURVE('E411',#612,#194,#618,.T.);
#620=ORIENTED_EDGE('',*,*,#619,.T.);
#621=EDGE_LOOP('',(#605,#606,#614,#620));
#622=FACE_BOUND('',#621,.T.);
#623=ADVANCED_FACE('F613',(#622),#604,.T.);
#624=CARTESIAN_POINT('',(15.1610542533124,50.,25.2996586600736));
#625=DIRECTION('',(0.,-1.,0.));
#626=DIRECTION('',(0.,0.,-1.));
#627=AXIS2_PLACEMENT_3D('',#624,#625,#626);
#628=CYLINDRICAL_SURFACE('',#627,2.53999999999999);
#629=ORIENTED_EDGE('',*,*,#204,.F.);
#630=ORIENTED_EDGE('',*,*,#619,.F.);
#631=CARTESIAN_POINT('',(15.1610542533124,50.,25.2996586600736));
#632=DIRECTION('',(0.,1.,0.));
#633=DIRECTION('',(0.,0.,1.));
#634=AXIS2_PLACEMENT_3D('',#631,#632,#633);
#635=CIRCLE('',#634,2.53999999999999);
#636=CARTESIAN_POINT('',(17.6484039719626,50.,25.8141403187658));
#637=VERTEX_POINT('',#636);
#638=EDGE_CURVE('E296',#612,#637,#635,.T.);
#639=ORIENTED_EDGE('',*,*,#638,.T.);
#640=DIRECTION('',(0.,-1.,0.));
#641=VECTOR('',#640,1.);
#642=CARTESIAN_POINT('',(17.6484039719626,50.,25.8141403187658));
#643=LINE('',#642,#641);
#644=EDGE_CURVE('E412',#637,#203,#643,.T.);
#645=ORIENTED_EDGE('',*,*,#644,.T.);
#646=EDGE_LOOP('',(#629,#630,#639,#645));
#647=FACE_BOUND('',#646,.T.);
#648=ADVANCED_FACE('F606',(#647),#628,.F.);
#649=CARTESIAN_POINT('',(27.4411193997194,50.,27.8396586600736));
#650=DIRECTION('',(0.,-1.,0.));
#651=DIRECTION('',(0.,0.,-1.));
#652=AXIS2_PLACEMENT_3D('',#649,#650,#651);
#653=CYLINDRICAL_SURFACE('',#652,10.);
#654=ORIENTED_EDGE('',*,*,#213,.F.);
#655=ORIENTED_EDGE('',*,*,#644,.F.);
#656=CARTESIAN_POINT('',(27.4411193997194,50.,27.8396586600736));
#657=DIRECTION('',(0.,-1.,0.));
#658=DIRECTION('',(0.,0.,1.));
#659=AXIS2_PLACEMENT_3D('',#656,#657,#658);
#660=CIRCLE('',#659,10.);
#661=CARTESIAN_POINT('',(25.4156010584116,50.,18.0469432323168));
#662=VERTEX_POINT('',#661);
#663=EDGE_CURVE('E301',#637,#662,#660,.T.);
#664=ORIENTED_EDGE('',*,*,#663,.T.);
#665=DIRECTION('',(0.,-1.,0.));
#666=VECTOR('',#665,1.);
#667=CARTESIAN_POINT('',(25.4156010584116,50.,18.0469432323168));
#668=LINE('',#667,#666);
#669=EDGE_CURVE('E413',#662,#212,#668,.T.);
#670=ORIENTED_EDGE('',*,*,#669,.T.);
#671=EDGE_LOOP('',(#654,#655,#664,#670));
#672=FACE_BOUND('',#671,.T.);
#673=ADVANCED_FACE('F608',(#672),#653,.T.);
#674=CARTESIAN_POINT('',(24.9011193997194,50.,15.5595935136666));
#675=DIRECTION('',(0.,-1.,0.));
#676=DIRECTION('',(0.,0.,-1.));
#677=AXIS2_PLACEMENT_3D('',#674,#675,#676);
#678=CYLINDRICAL_SURFACE('',#677,2.53999999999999);
#679=ORIENTED_EDGE('',*,*,#222,.F.);
#680=ORIENTED_EDGE('',*,*,#669,.F.);
#681=CARTESIAN_POINT('',(24.9011193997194,50.,15.5595935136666));
#682=DIRECTION('',(0.,1.,0.));
#683=DIRECTION('',(0.,0.,1.));
#684=AXIS2_PLACEMENT_3D('',#681,#682,#683);
#685=CIRCLE('',#684,2.53999999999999);
#686=CARTESIAN_POINT('',(27.4411193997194,50.,15.5595935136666));
#687=VERTEX_POINT('',#686);
#688=EDGE_CURVE('E302',#662,#687,#685,.T.);
#689=ORIENTED_EDGE('',*,*,#688,.T.);
#690=DIRECTION('',(0.,-1.,0.));
#691=VECTOR('',#690,1.);
#692=CARTESIAN_POINT('',(27.4411193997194,50.,15.5595935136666));
#693=LINE('',#692,#691);
#694=EDGE_CURVE('E408',#687,#221,#693,.T.);
#695=ORIENTED_EDGE('',*,*,#694,.T.);
#696=EDGE_LOOP('',(#679,#680,#689,#695));
#697=FACE_BOUND('',#696,.T.);
#698=ADVANCED_FACE('F601',(#697),#678,.F.);
#699=CARTESIAN_POINT('',(27.4411193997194,50.,15.5595935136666));
#700=DIRECTION('',(-1.,0.,0.));
#701=DIRECTION('',(0.,0.,1.));
#702=AXIS2_PLACEMENT_3D('',#699,#700,#701);
#703=PLANE('',#702);
#704=ORIENTED_EDGE('',*,*,#230,.F.);
#705=ORIENTED_EDGE('',*,*,#694,.F.);
#706=DIRECTION('',(0.,0.,-1.));
#707=VECTOR('',#706,1.);
#708=CARTESIAN_POINT('',(27.4411193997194,50.,15.5595935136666));
#709=LINE('',#708,#707);
#710=CARTESIAN_POINT('',(27.4411193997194,50.,-15.8802761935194));
#711=VERTEX_POINT('',#710);
#712=EDGE_CURVE('E310',#687,#711,#709,.T.);
#713=ORIENTED_EDGE('',*,*,#712,.T.);
#714=DIRECTION('',(0.,-1.,0.));
#715=VECTOR('',#714,1.);
#716=CARTESIAN_POINT('',(27.4411193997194,50.,-15.8802761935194));
#717=LINE('',#716,#715);
#718=EDGE_CURVE('E406',#711,#229,#717,.T.);
#719=ORIENTED_EDGE('',*,*,#718,.T.);
#720=EDGE_LOOP('',(#704,#705,#713,#719));
#721=FACE_BOUND('',#720,.T.);
#722=ADVANCED_FACE('F596',(#721),#703,.T.);
#723=CARTESIAN_POINT('',(24.9011193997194,50.,-15.8802761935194));
#724=DIRECTION('',(0.,-1.,0.));
#725=DIRECTION('',(0.,0.,-1.));
#726=AXIS2_PLACEMENT_3D('',#723,#724,#725);
#727=CYLINDRICAL_SURFACE('',#726,2.53999999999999);
#728=ORIENTED_EDGE('',*,*,#239,.F.);
#729=ORIENTED_EDGE('',*,*,#718,.F.);
#730=CARTESIAN_POINT('',(24.9011193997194,50.,-15.8802761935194));
#731=DIRECTION('',(0.,1.,0.));
#732=DIRECTION('',(0.,0.,1.));
#733=AXIS2_PLACEMENT_3D('',#730,#731,#732);
#734=CIRCLE('',#733,2.53999999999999);
#735=CARTESIAN_POINT('',(25.4156010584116,50.,-18.3676259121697));
#736=VERTEX_POINT('',#735);
#737=EDGE_CURVE('E309',#711,#736,#734,.T.);
#738=ORIENTED_EDGE('',*,*,#737,.T.);
#739=DIRECTION('',(0.,-1.,0.));
#740=VECTOR('',#739,1.);
#741=CARTESIAN_POINT('',(25.4156010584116,50.,-18.3676259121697));
#742=LINE('',#741,#740);
#743=EDGE_CURVE('E403',#736,#238,#742,.T.);
#744=ORIENTED_EDGE('',*,*,#743,.T.);
#745=EDGE_LOOP('',(#728,#729,#738,#744));
#746=FACE_BOUND('',#745,.T.);
#747=ADVANCED_FACE('F593',(#746),#727,.F.);
#748=CARTESIAN_POINT('',(27.4411193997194,50.,-28.1603413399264));
#749=DIRECTION('',(0.,-1.,0.));
#750=DIRECTION('',(0.,0.,-1.));
#751=AXIS2_PLACEMENT_3D('',#748,#749,#750);
#752=CYLINDRICAL_SURFACE('',#751,10.);
#753=ORIENTED_EDGE('',*,*,#248,.F.);
#754=ORIENTED_EDGE('',*,*,#743,.F.);
#755=CARTESIAN_POINT('',(27.4411193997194,50.,-28.1603413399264));
#756=DIRECTION('',(0.,-1.,0.));
#757=DIRECTION('',(0.,0.,1.));
#758=AXIS2_PLACEMENT_3D('',#755,#756,#757);
#759=CIRCLE('',#758,10.);
#760=CARTESIAN_POINT('',(17.6484039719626,50.,-26.1348229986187));
#761=VERTEX_POINT('',#760);
#762=EDGE_CURVE('E312',#736,#761,#759,.T.);
#763=ORIENTED_EDGE('',*,*,#762,.T.);
#764=DIRECTION('',(0.,-1.,0.));
#765=VECTOR('',#764,1.);
#766=CARTESIAN_POINT('',(17.6484039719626,50.,-26.1348229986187));
#767=LINE('',#766,#765);
#768=EDGE_CURVE('E401',#761,#247,#767,.T.);
#769=ORIENTED_EDGE('',*,*,#768,.T.);
#770=EDGE_LOOP('',(#753,#754,#763,#769));
#771=FACE_BOUND('',#770,.T.);
#772=ADVANCED_FACE('F586',(#771),#752,.T.);
#773=CARTESIAN_POINT('',(15.1610542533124,50.,-25.6203413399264));
#774=DIRECTION('',(0.,-1.,0.));
#775=DIRECTION('',(0.,0.,-1.));
#776=AXIS2_PLACEMENT_3D('',#773,#774,#775);
#777=CYLINDRICAL_SURFACE('',#776,2.53999999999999);
#778=ORIENTED_EDGE('',*,*,#257,.F.);
#779=ORIENTED_EDGE('',*,*,#768,.F.);
#780=CARTESIAN_POINT('',(15.1610542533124,50.,-25.6203413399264));
#781=DIRECTION('',(0.,1.,0.));
#782=DIRECTION('',(0.,0.,1.));
#783=AXIS2_PLACEMENT_3D('',#780,#781,#782);
#784=CIRCLE('',#783,2.53999999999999);
#785=CARTESIAN_POINT('',(15.1610542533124,50.,-28.1603413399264));
#786=VERTEX_POINT('',#785);
#787=EDGE_CURVE('E317',#761,#786,#784,.T.);
#788=ORIENTED_EDGE('',*,*,#787,.T.);
#789=DIRECTION('',(0.,-1.,0.));
#790=VECTOR('',#789,1.);
#791=CARTESIAN_POINT('',(15.1610542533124,50.,-28.1603413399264));
#792=LINE('',#791,#790);
#793=EDGE_CURVE('E402',#786,#256,#792,.T.);
#794=ORIENTED_EDGE('',*,*,#793,.T.);
#795=EDGE_LOOP('',(#778,#779,#788,#794));
#796=FACE_BOUND('',#795,.T.);
#797=ADVANCED_FACE('F588',(#796),#777,.F.);
#798=CARTESIAN_POINT('',(15.1610542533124,50.,-28.1603413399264));
#799=DIRECTION('',(0.,0.,1.));
#800=DIRECTION('',(1.,0.,0.));
#801=AXIS2_PLACEMENT_3D('',#798,#799,#800);
#802=PLANE('',#801);
#803=ORIENTED_EDGE('',*,*,#265,.F.);
#804=ORIENTED_EDGE('',*,*,#793,.F.);
#805=DIRECTION('',(-1.,0.,0.));
#806=VECTOR('',#805,1.);
#807=CARTESIAN_POINT('',(15.1610542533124,50.,-28.1603413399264));
#808=LINE('',#807,#806);
#809=CARTESIAN_POINT('',(-16.2788154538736,50.,-28.1603413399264));
#810=VERTEX_POINT('',#809);
#811=EDGE_CURVE('E316',#786,#810,#808,.T.);
#812=ORIENTED_EDGE('',*,*,#811,.T.);
#813=DIRECTION('',(0.,-1.,0.));
#814=VECTOR('',#813,1.);
#815=CARTESIAN_POINT('',(-16.2788154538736,50.,-28.1603413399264));
#816=LINE('',#815,#814);
#817=EDGE_CURVE('E398',#810,#264,#816,.T.);
#818=ORIENTED_EDGE('',*,*,#817,.T.);
#819=EDGE_LOOP('',(#803,#804,#812,#818));
#820=FACE_BOUND('',#819,.T.);
#821=ADVANCED_FACE('F581',(#820),#802,.T.);
#822=CARTESIAN_POINT('',(-16.2788154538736,50.,-25.6203413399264));
#823=DIRECTION('',(0.,-1.,0.));
#824=DIRECTION('',(0.,0.,-1.));
#825=AXIS2_PLACEMENT_3D('',#822,#823,#824);
#826=CYLINDRICAL_SURFACE('',#825,2.53999999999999);
#827=ORIENTED_EDGE('',*,*,#274,.F.);
#828=ORIENTED_EDGE('',*,*,#817,.F.);
#829=CARTESIAN_POINT('',(-16.2788154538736,50.,-25.6203413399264));
#830=DIRECTION('',(0.,1.,0.));
#831=DIRECTION('',(0.,0.,1.));
#832=AXIS2_PLACEMENT_3D('',#829,#830,#831);
#833=CIRCLE('',#832,2.53999999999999);
#834=CARTESIAN_POINT('',(-18.7661651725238,50.,-26.1348229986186));
#835=VERTEX_POINT('',#834);
#836=EDGE_CURVE('E321',#810,#835,#833,.T.);
#837=ORIENTED_EDGE('',*,*,#836,.T.);
#838=DIRECTION('',(0.,-1.,0.));
#839=VECTOR('',#838,1.);
#840=CARTESIAN_POINT('',(-18.7661651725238,50.,-26.1348229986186));
#841=LINE('',#840,#839);
#842=EDGE_CURVE('E397',#835,#273,#841,.T.);
#843=ORIENTED_EDGE('',*,*,#842,.T.);
#844=EDGE_LOOP('',(#827,#828,#837,#843));
#845=FACE_BOUND('',#844,.T.);
#846=ADVANCED_FACE('F579',(#845),#826,.F.);
#847=CARTESIAN_POINT('',(-28.5588806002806,50.,-28.1603413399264));
#848=DIRECTION('',(0.,-1.,0.));
#849=DIRECTION('',(0.,0.,-1.));
#850=AXIS2_PLACEMENT_3D('',#847,#848,#849);
#851=CYLINDRICAL_SURFACE('',#850,10.);
#852=ORIENTED_EDGE('',*,*,#283,.F.);
#853=ORIENTED_EDGE('',*,*,#842,.F.);
#854=CARTESIAN_POINT('',(-28.5588806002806,50.,-28.1603413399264));
#855=DIRECTION('',(0.,-1.,0.));
#856=DIRECTION('',(0.,0.,1.));
#857=AXIS2_PLACEMENT_3D('',#854,#855,#856);
#858=CIRCLE('',#857,10.);
#859=CARTESIAN_POINT('',(-26.5333622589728,50.,-18.3676259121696));
#860=VERTEX_POINT('',#859);
#861=EDGE_CURVE('E322',#835,#860,#858,.T.);
#862=ORIENTED_EDGE('',*,*,#861,.T.);
#863=DIRECTION('',(0.,-1.,0.));
#864=VECTOR('',#863,1.);
#865=CARTESIAN_POINT('',(-26.5333622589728,50.,-18.3676259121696));
#866=LINE('',#865,#864);
#867=EDGE_CURVE('E391',#860,#282,#866,.T.);
#868=ORIENTED_EDGE('',*,*,#867,.T.);
#869=EDGE_LOOP('',(#852,#853,#862,#868));
#870=FACE_BOUND('',#869,.T.);
#871=ADVANCED_FACE('F573',(#870),#851,.T.);
#872=CARTESIAN_POINT('',(-26.0188806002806,50.,-15.8802761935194));
#873=DIRECTION('',(0.,-1.,0.));
#874=DIRECTION('',(0.,0.,-1.));
#875=AXIS2_PLACEMENT_3D('',#872,#873,#874);
#876=CYLINDRICAL_SURFACE('',#875,2.53999999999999);
#877=ORIENTED_EDGE('',*,*,#292,.F.);
#878=ORIENTED_EDGE('',*,*,#867,.F.);
#879=CARTESIAN_POINT('',(-26.0188806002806,50.,-15.8802761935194));
#880=DIRECTION('',(0.,1.,0.));
#881=DIRECTION('',(0.,0.,1.));
#882=AXIS2_PLACEMENT_3D('',#879,#880,#881);
#883=CIRCLE('',#882,2.53999999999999);
#884=CARTESIAN_POINT('',(-28.5588806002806,50.,-15.8802761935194));
#885=VERTEX_POINT('',#884);
#886=EDGE_CURVE('E327',#860,#885,#883,.T.);
#887=ORIENTED_EDGE('',*,*,#886,.T.);
#888=DIRECTION('',(0.,-1.,0.));
#889=VECTOR('',#888,1.);
#890=CARTESIAN_POINT('',(-28.5588806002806,50.,-15.8802761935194));
#891=LINE('',#890,#889);
#892=EDGE_CURVE('E392',#885,#291,#891,.T.);
#893=ORIENTED_EDGE('',*,*,#892,.T.);
#894=EDGE_LOOP('',(#877,#878,#887,#893));
#895=FACE_BOUND('',#894,.T.);
#896=ADVANCED_FACE('F569',(#895),#876,.F.);
#897=CARTESIAN_POINT('',(-28.5588806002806,50.,-15.8802761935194));
#898=DIRECTION('',(1.,0.,0.));
#899=DIRECTION('',(0.,0.,-1.));
#900=AXIS2_PLACEMENT_3D('',#897,#898,#899);
#901=PLANE('',#900);
#902=ORIENTED_EDGE('',*,*,#300,.F.);
#903=ORIENTED_EDGE('',*,*,#892,.F.);
#904=DIRECTION('',(0.,0.,1.));
#905=VECTOR('',#904,1.);
#906=CARTESIAN_POINT('',(-28.5588806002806,50.,-15.8802761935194));
#907=LINE('',#906,#905);
#908=CARTESIAN_POINT('',(-28.5588806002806,50.,15.5595935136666));
#909=VERTEX_POINT('',#908);
#910=EDGE_CURVE('E331',#885,#909,#907,.T.);
#911=ORIENTED_EDGE('',*,*,#910,.T.);
#912=DIRECTION('',(0.,-1.,0.));
#913=VECTOR('',#912,1.);
#914=CARTESIAN_POINT('',(-28.5588806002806,50.,15.5595935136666));
#915=LINE('',#914,#913);
#916=EDGE_CURVE('E393',#909,#299,#915,.T.);
#917=ORIENTED_EDGE('',*,*,#916,.T.);
#918=EDGE_LOOP('',(#902,#903,#911,#917));
#919=FACE_BOUND('',#918,.T.);
#920=ADVANCED_FACE('F566',(#919),#901,.T.);
#921=CARTESIAN_POINT('',(-26.0188806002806,50.,15.5595935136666));
#922=DIRECTION('',(0.,-1.,0.));
#923=DIRECTION('',(0.,0.,-1.));
#924=AXIS2_PLACEMENT_3D('',#921,#922,#923);
#925=CYLINDRICAL_SURFACE('',#924,2.53999999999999);
#926=ORIENTED_EDGE('',*,*,#309,.F.);
#927=ORIENTED_EDGE('',*,*,#916,.F.);
#928=CARTESIAN_POINT('',(-26.0188806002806,50.,15.5595935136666));
#929=DIRECTION('',(0.,1.,0.));
#930=DIRECTION('',(0.,0.,1.));
#931=AXIS2_PLACEMENT_3D('',#928,#929,#930);
#932=CIRCLE('',#931,2.53999999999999);
#933=CARTESIAN_POINT('',(-26.5333622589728,50.,18.0469432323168));
#934=VERTEX_POINT('',#933);
#935=EDGE_CURVE('E333',#909,#934,#932,.T.);
#936=ORIENTED_EDGE('',*,*,#935,.T.);
#937=DIRECTION('',(0.,-1.,0.));
#938=VECTOR('',#937,1.);
#939=CARTESIAN_POINT('',(-26.5333622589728,50.,18.0469432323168));
#940=LINE('',#939,#938);
#941=EDGE_CURVE('E388',#934,#308,#940,.T.);
#942=ORIENTED_EDGE('',*,*,#941,.T.);
#943=EDGE_LOOP('',(#926,#927,#936,#942));
#944=FACE_BOUND('',#943,.T.);
#945=ADVANCED_FACE('F565',(#944),#925,.F.);
#946=CARTESIAN_POINT('',(-28.5588806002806,50.,27.8396586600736));
#947=DIRECTION('',(0.,-1.,0.));
#948=DIRECTION('',(0.,0.,-1.));
#949=AXIS2_PLACEMENT_3D('',#946,#947,#948);
#950=CYLINDRICAL_SURFACE('',#949,10.);
#951=ORIENTED_EDGE('',*,*,#316,.F.);
#952=ORIENTED_EDGE('',*,*,#941,.F.);
#953=CARTESIAN_POINT('',(-28.5588806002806,50.,27.8396586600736));
#954=DIRECTION('',(0.,-1.,0.));
#955=DIRECTION('',(0.,0.,1.));
#956=AXIS2_PLACEMENT_3D('',#953,#954,#955);
#957=CIRCLE('',#956,10.);
#958=EDGE_CURVE('E340',#934,#579,#957,.T.);
#959=ORIENTED_EDGE('',*,*,#958,.T.);
#960=ORIENTED_EDGE('',*,*,#580,.T.);
#961=EDGE_LOOP('',(#951,#952,#959,#960));
#962=FACE_BOUND('',#961,.T.);
#963=ADVANCED_FACE('F556',(#962),#950,.T.);
#964=CARTESIAN_POINT('',(0.,50.,0.));
#965=DIRECTION('',(0.,1.,0.));
#966=DIRECTION('',(0.,0.,1.));
#967=AXIS2_PLACEMENT_3D('',#964,#965,#966);
#968=PLANE('',#967);
#969=ORIENTED_EDGE('',*,*,#613,.F.);
#970=ORIENTED_EDGE('',*,*,#589,.F.);
#971=ORIENTED_EDGE('',*,*,#958,.F.);
#972=ORIENTED_EDGE('',*,*,#935,.F.);
#973=ORIENTED_EDGE('',*,*,#910,.F.);
#974=ORIENTED_EDGE('',*,*,#886,.F.);
#975=ORIENTED_EDGE('',*,*,#861,.F.);
#976=ORIENTED_EDGE('',*,*,#836,.F.);
#977=ORIENTED_EDGE('',*,*,#811,.F.);
#978=ORIENTED_EDGE('',*,*,#787,.F.);
#979=ORIENTED_EDGE('',*,*,#762,.F.);
#980=ORIENTED_EDGE('',*,*,#737,.F.);
#981=ORIENTED_EDGE('',*,*,#712,.F.);
#982=ORIENTED_EDGE('',*,*,#688,.F.);
#983=ORIENTED_EDGE('',*,*,#663,.F.);
#984=ORIENTED_EDGE('',*,*,#638,.F.);
#985=EDGE_LOOP('',(#969,#970,#971,#972,#973,#974,#975,#976,#977,#978,#979,#980,#981,#982,#983,#984));
#986=FACE_BOUND('',#985,.T.);
#987=ADVANCED_FACE('F558',(#986),#968,.F.);
#988=CARTESIAN_POINT('',(25.,220.,0.));
#989=DIRECTION('',(-1.,0.,0.));
#990=DIRECTION('',(0.,0.,1.));
#991=AXIS2_PLACEMENT_3D('',#988,#989,#990);
#992=PLANE('',#991);
#993=CARTESIAN_POINT('',(25.,80.,0.));
#994=DIRECTION('',(-1.,0.,0.));
#995=DIRECTION('',(0.,0.,1.));
#996=AXIS2_PLACEMENT_3D('',#993,#994,#995);
#997=CIRCLE('',#996,10.);
#998=CARTESIAN_POINT('',(25.,80.,10.));
#999=VERTEX_POINT('',#998);
#1000=EDGE_CURVE('E466',#999,#999,#997,.T.);
#1001=ORIENTED_EDGE('',*,*,#1000,.F.);
#1002=EDGE_LOOP('',(#1001));
#1003=FACE_BOUND('',#1002,.T.);
#1004=CARTESIAN_POINT('',(25.,190.,0.));
#1005=DIRECTION('',(-1.,0.,0.));
#1006=DIRECTION('',(0.,0.,1.));
#1007=AXIS2_PLACEMENT_3D('',#1004,#1005,#1006);
#1008=CIRCLE('',#1007,10.);
#1009=CARTESIAN_POINT('',(25.,190.,10.));
#1010=VERTEX_POINT('',#1009);
#1011=EDGE_CURVE('E464',#1010,#1010,#1008,.T.);
#1012=ORIENTED_EDGE('',*,*,#1011,.F.);
#1013=EDGE_LOOP('',(#1012));
#1014=FACE_BOUND('',#1013,.T.);
#1015=DIRECTION('',(0.,0.,-1.));
#1016=VECTOR('',#1015,1.);
#1017=CARTESIAN_POINT('',(25.,220.,0.));
#1018=LINE('',#1017,#1016);
#1019=CARTESIAN_POINT('',(25.,220.,25.));
#1020=VERTEX_POINT('',#1019);
#1021=CARTESIAN_POINT('',(25.,220.,-25.));
#1022=VERTEX_POINT('',#1021);
#1023=EDGE_CURVE('E248',#1020,#1022,#1018,.T.);
#1024=ORIENTED_EDGE('',*,*,#1023,.T.);
#1025=CARTESIAN_POINT('',(25.,210.,-25.));
#1026=DIRECTION('',(-1.,0.,0.));
#1027=DIRECTION('',(0.,0.,1.));
#1028=AXIS2_PLACEMENT_3D('',#1025,#1026,#1027);
#1029=CIRCLE('',#1028,10.);
#1030=EDGE_CURVE('E475',#1022,#409,#1029,.T.);
#1031=ORIENTED_EDGE('',*,*,#1030,.T.);
#1032=ORIENTED_EDGE('',*,*,#410,.T.);
#1033=ORIENTED_EDGE('',*,*,#40,.F.);
#1034=DIRECTION('',(0.,-1.,0.));
#1035=VECTOR('',#1034,1.);
#1036=CARTESIAN_POINT('',(25.,220.,25.));
#1037=LINE('',#1036,#1035);
#1038=EDGE_CURVE('E258',#1020,#31,#1037,.T.);
#1039=ORIENTED_EDGE('',*,*,#1038,.F.);
#1040=EDGE_LOOP('',(#1024,#1031,#1032,#1033,#1039));
#1041=FACE_BOUND('',#1040,.T.);
#1042=ADVANCED_FACE('F257',(#1003,#1014,#1041),#992,.T.);
#1043=CARTESIAN_POINT('',(0.,220.,25.));
#1044=DIRECTION('',(0.,0.,-1.));
#1045=DIRECTION('',(-1.,0.,0.));
#1046=AXIS2_PLACEMENT_3D('',#1043,#1044,#1045);
#1047=PLANE('',#1046);
#1048=ORIENTED_EDGE('',*,*,#32,.F.);
#1049=DIRECTION('',(0.,-1.,0.));
#1050=VECTOR('',#1049,1.);
#1051=CARTESIAN_POINT('',(-25.,220.,25.0000000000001));
#1052=LINE('',#1051,#1050);
#1053=CARTESIAN_POINT('',(-25.,220.,25.0000000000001));
#1054=VERTEX_POINT('',#1053);
#1055=EDGE_CURVE('E267',#1054,#29,#1052,.T.);
#1056=ORIENTED_EDGE('',*,*,#1055,.F.);
#1057=DIRECTION('',(1.,0.,0.));
#1058=VECTOR('',#1057,1.);
#1059=CARTESIAN_POINT('',(0.,220.,25.));
#1060=LINE('',#1059,#1058);
#1061=EDGE_CURVE('E231',#1054,#1020,#1060,.T.);
#1062=ORIENTED_EDGE('',*,*,#1061,.T.);
#1063=ORIENTED_EDGE('',*,*,#1038,.T.);
#1064=EDGE_LOOP('',(#1048,#1056,#1062,#1063));
#1065=FACE_BOUND('',#1064,.T.);
#1066=ADVANCED_FACE('F270',(#1065),#1047,.T.);
#1067=CARTESIAN_POINT('',(-25.,220.,0.));
#1068=DIRECTION('',(1.,0.,0.));
#1069=DIRECTION('',(0.,0.,-1.));
#1070=AXIS2_PLACEMENT_3D('',#1067,#1068,#1069);
#1071=PLANE('',#1070);
#1072=CARTESIAN_POINT('',(-25.,80.,0.));
#1073=DIRECTION('',(1.,0.,0.));
#1074=DIRECTION('',(0.,0.,-1.));
#1075=AXIS2_PLACEMENT_3D('',#1072,#1073,#1074);
#1076=CIRCLE('',#1075,10.);
#1077=CARTESIAN_POINT('',(-25.,80.,-10.));
#1078=VERTEX_POINT('',#1077);
#1079=EDGE_CURVE('E465',#1078,#1078,#1076,.T.);
#1080=ORIENTED_EDGE('',*,*,#1079,.F.);
#1081=EDGE_LOOP('',(#1080));
#1082=FACE_BOUND('',#1081,.T.);
#1083=CARTESIAN_POINT('',(-25.,190.,0.));
#1084=DIRECTION('',(1.,0.,0.));
#1085=DIRECTION('',(0.,0.,-1.));
#1086=AXIS2_PLACEMENT_3D('',#1083,#1084,#1085);
#1087=CIRCLE('',#1086,10.);
#1088=CARTESIAN_POINT('',(-25.,190.,-10.));
#1089=VERTEX_POINT('',#1088);
#1090=EDGE_CURVE('E456',#1089,#1089,#1087,.T.);
#1091=ORIENTED_EDGE('',*,*,#1090,.F.);
#1092=EDGE_LOOP('',(#1091));
#1093=FACE_BOUND('',#1092,.T.);
#1094=ORIENTED_EDGE('',*,*,#473,.F.);
#1095=CARTESIAN_POINT('',(-25.,210.,-25.));
#1096=DIRECTION('',(1.,0.,0.));
#1097=DIRECTION('',(0.,0.,-1.));
#1098=AXIS2_PLACEMENT_3D('',#1095,#1096,#1097);
#1099=CIRCLE('',#1098,10.);
#1100=CARTESIAN_POINT('',(-25.,220.,-25.));
#1101=VERTEX_POINT('',#1100);
#1102=EDGE_CURVE('E49',#466,#1101,#1099,.T.);
#1103=ORIENTED_EDGE('',*,*,#1102,.T.);
#1104=DIRECTION('',(0.,0.,1.));
#1105=VECTOR('',#1104,1.);
#1106=CARTESIAN_POINT('',(-25.,220.,0.));
#1107=LINE('',#1106,#1105);
#1108=EDGE_CURVE('E275',#1101,#1054,#1107,.T.);
#1109=ORIENTED_EDGE('',*,*,#1108,.T.);
#1110=ORIENTED_EDGE('',*,*,#1055,.T.);
#1111=ORIENTED_EDGE('',*,*,#54,.F.);
#1112=EDGE_LOOP('',(#1094,#1103,#1109,#1110,#1111));
#1113=FACE_BOUND('',#1112,.T.);
#1114=ADVANCED_FACE('F690',(#1082,#1093,#1113),#1071,.T.);
#1115=CARTESIAN_POINT('',(65.,190.,0.));
#1116=DIRECTION('',(-1.,0.,0.));
#1117=DIRECTION('',(0.,0.,1.));
#1118=AXIS2_PLACEMENT_3D('',#1115,#1116,#1117);
#1119=CYLINDRICAL_SURFACE('',#1118,10.);
#1120=ORIENTED_EDGE('',*,*,#1090,.T.);
#1121=EDGE_LOOP('',(#1120));
#1122=FACE_BOUND('',#1121,.T.);
#1123=ORIENTED_EDGE('',*,*,#503,.T.);
#1124=EDGE_LOOP('',(#1123));
#1125=FACE_BOUND('',#1124,.T.);
#1126=ADVANCED_FACE('F538',(#1122,#1125),#1119,.F.);
#1127=CARTESIAN_POINT('',(65.,80.,0.));
#1128=DIRECTION('',(-1.,0.,0.));
#1129=DIRECTION('',(0.,0.,1.));
#1130=AXIS2_PLACEMENT_3D('',#1127,#1128,#1129);
#1131=CYLINDRICAL_SURFACE('',#1130,10.);
#1132=ORIENTED_EDGE('',*,*,#1079,.T.);
#1133=EDGE_LOOP('',(#1132));
#1134=FACE_BOUND('',#1133,.T.);
#1135=ORIENTED_EDGE('',*,*,#492,.T.);
#1136=EDGE_LOOP('',(#1135));
#1137=FACE_BOUND('',#1136,.T.);
#1138=ADVANCED_FACE('F529',(#1134,#1137),#1131,.F.);
#1139=ORIENTED_EDGE('',*,*,#1011,.T.);
#1140=EDGE_LOOP('',(#1139));
#1141=FACE_BOUND('',#1140,.T.);
#1142=ORIENTED_EDGE('',*,*,#376,.F.);
#1143=EDGE_LOOP('',(#1142));
#1144=FACE_BOUND('',#1143,.T.);
#1145=ADVANCED_FACE('F521',(#1141,#1144),#1119,.F.);
#1146=ORIENTED_EDGE('',*,*,#1000,.T.);
#1147=EDGE_LOOP('',(#1146));
#1148=FACE_BOUND('',#1147,.T.);
#1149=ORIENTED_EDGE('',*,*,#365,.F.);
#1150=EDGE_LOOP('',(#1149));
#1151=FACE_BOUND('',#1150,.T.);
#1152=ADVANCED_FACE('F524',(#1148,#1151),#1131,.F.);
#1153=CARTESIAN_POINT('',(-24.0588806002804,50.,23.3396586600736));
#1154=DIRECTION('',(0.,-1.,0.));
#1155=DIRECTION('',(0.,0.,-1.));
#1156=AXIS2_PLACEMENT_3D('',#1153,#1154,#1155);
#1157=CYLINDRICAL_SURFACE('',#1156,2.5);
#1158=CARTESIAN_POINT('',(-24.0588806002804,50.,23.3396586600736));
#1159=DIRECTION('',(0.,-1.,0.));
#1160=DIRECTION('',(0.,0.,-1.));
#1161=AXIS2_PLACEMENT_3D('',#1158,#1159,#1160);
#1162=CIRCLE('',#1161,2.5);
#1163=CARTESIAN_POINT('',(-24.0588806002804,50.,20.8396586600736));
#1164=VERTEX_POINT('',#1163);
#1165=EDGE_CURVE('E497',#1164,#1164,#1162,.T.);
#1166=ORIENTED_EDGE('',*,*,#1165,.F.);
#1167=EDGE_LOOP('',(#1166));
#1168=FACE_BOUND('',#1167,.T.);
#1169=ORIENTED_EDGE('',*,*,#104,.T.);
#1170=EDGE_LOOP('',(#1169));
#1171=FACE_BOUND('',#1170,.T.);
#1172=ADVANCED_FACE('F525',(#1168,#1171),#1157,.F.);
#1173=CARTESIAN_POINT('',(-24.0588806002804,50.,23.3396586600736));
#1174=DIRECTION('',(0.,-1.,0.));
#1175=DIRECTION('',(0.,0.,-1.));
#1176=AXIS2_PLACEMENT_3D('',#1173,#1174,#1175);
#1177=PLANE('',#1176);
#1178=ORIENTED_EDGE('',*,*,#1165,.T.);
#1179=EDGE_LOOP('',(#1178));
#1180=FACE_BOUND('',#1179,.T.);
#1181=ADVANCED_FACE('F534',(#1180),#1177,.T.);
#1182=CARTESIAN_POINT('',(22.9411193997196,50.,23.3396586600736));
#1183=DIRECTION('',(0.,-1.,0.));
#1184=DIRECTION('',(0.,0.,-1.));
#1185=AXIS2_PLACEMENT_3D('',#1182,#1183,#1184);
#1186=CYLINDRICAL_SURFACE('',#1185,2.5);
#1187=CARTESIAN_POINT('',(22.9411193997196,50.,23.3396586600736));
#1188=DIRECTION('',(0.,-1.,0.));
#1189=DIRECTION('',(0.,0.,-1.));
#1190=AXIS2_PLACEMENT_3D('',#1187,#1188,#1189);
#1191=CIRCLE('',#1190,2.5);
#1192=CARTESIAN_POINT('',(22.9411193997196,50.,20.8396586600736));
#1193=VERTEX_POINT('',#1192);
#1194=EDGE_CURVE('E1129',#1193,#1193,#1191,.T.);
#1195=ORIENTED_EDGE('',*,*,#1194,.F.);
#1196=EDGE_LOOP('',(#1195));
#1197=FACE_BOUND('',#1196,.T.);
#1198=ORIENTED_EDGE('',*,*,#93,.T.);
#1199=EDGE_LOOP('',(#1198));
#1200=FACE_BOUND('',#1199,.T.);
#1201=ADVANCED_FACE('F803',(#1197,#1200),#1186,.F.);
#1202=CARTESIAN_POINT('',(22.9411193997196,50.,23.3396586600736));
#1203=DIRECTION('',(0.,-1.,0.));
#1204=DIRECTION('',(0.,0.,-1.));
#1205=AXIS2_PLACEMENT_3D('',#1202,#1203,#1204);
#1206=PLANE('',#1205);
#1207=ORIENTED_EDGE('',*,*,#1194,.T.);
#1208=EDGE_LOOP('',(#1207));
#1209=FACE_BOUND('',#1208,.T.);
#1210=ADVANCED_FACE('F795',(#1209),#1206,.T.);
#1211=CARTESIAN_POINT('',(22.9411193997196,50.,-23.6603413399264));
#1212=DIRECTION('',(0.,-1.,0.));
#1213=DIRECTION('',(0.,0.,-1.));
#1214=AXIS2_PLACEMENT_3D('',#1211,#1212,#1213);
#1215=CYLINDRICAL_SURFACE('',#1214,2.5);
#1216=CARTESIAN_POINT('',(22.9411193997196,50.,-23.6603413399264));
#1217=DIRECTION('',(0.,-1.,0.));
#1218=DIRECTION('',(0.,0.,-1.));
#1219=AXIS2_PLACEMENT_3D('',#1216,#1217,#1218);
#1220=CIRCLE('',#1219,2.5);
#1221=CARTESIAN_POINT('',(22.9411193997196,50.,-26.1603413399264));
#1222=VERTEX_POINT('',#1221);
#1223=EDGE_CURVE('E492',#1222,#1222,#1220,.T.);
#1224=ORIENTED_EDGE('',*,*,#1223,.F.);
#1225=EDGE_LOOP('',(#1224));
#1226=FACE_BOUND('',#1225,.T.);
#1227=ORIENTED_EDGE('',*,*,#82,.T.);
#1228=EDGE_LOOP('',(#1227));
#1229=FACE_BOUND('',#1228,.T.);
#1230=ADVANCED_FACE('F782',(#1226,#1229),#1215,.F.);
#1231=CARTESIAN_POINT('',(22.9411193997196,50.,-23.6603413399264));
#1232=DIRECTION('',(0.,-1.,0.));
#1233=DIRECTION('',(0.,0.,-1.));
#1234=AXIS2_PLACEMENT_3D('',#1231,#1232,#1233);
#1235=PLANE('',#1234);
#1236=ORIENTED_EDGE('',*,*,#1223,.T.);
#1237=EDGE_LOOP('',(#1236));
#1238=FACE_BOUND('',#1237,.T.);
#1239=ADVANCED_FACE('F771',(#1238),#1235,.T.);
#1240=CARTESIAN_POINT('',(-24.0588806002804,50.,-23.6603413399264));
#1241=DIRECTION('',(0.,-1.,0.));
#1242=DIRECTION('',(0.,0.,-1.));
#1243=AXIS2_PLACEMENT_3D('',#1240,#1241,#1242);
#1244=CYLINDRICAL_SURFACE('',#1243,2.5);
#1245=CARTESIAN_POINT('',(-24.0588806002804,50.,-23.6603413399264));
#1246=DIRECTION('',(0.,-1.,0.));
#1247=DIRECTION('',(0.,0.,-1.));
#1248=AXIS2_PLACEMENT_3D('',#1245,#1246,#1247);
#1249=CIRCLE('',#1248,2.5);
#1250=CARTESIAN_POINT('',(-24.0588806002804,50.,-26.1603413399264));
#1251=VERTEX_POINT('',#1250);
#1252=EDGE_CURVE('E485',#1251,#1251,#1249,.T.);
#1253=ORIENTED_EDGE('',*,*,#1252,.F.);
#1254=EDGE_LOOP('',(#1253));
#1255=FACE_BOUND('',#1254,.T.);
#1256=ORIENTED_EDGE('',*,*,#71,.T.);
#1257=EDGE_LOOP('',(#1256));
#1258=FACE_BOUND('',#1257,.T.);
#1259=ADVANCED_FACE('F764',(#1255,#1258),#1244,.F.);
#1260=CARTESIAN_POINT('',(-24.0588806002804,50.,-23.6603413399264));
#1261=DIRECTION('',(0.,-1.,0.));
#1262=DIRECTION('',(0.,0.,-1.));
#1263=AXIS2_PLACEMENT_3D('',#1260,#1261,#1262);
#1264=PLANE('',#1263);
#1265=ORIENTED_EDGE('',*,*,#1252,.T.);
#1266=EDGE_LOOP('',(#1265));
#1267=FACE_BOUND('',#1266,.T.);
#1268=ADVANCED_FACE('F670',(#1267),#1264,.T.);
#1269=CARTESIAN_POINT('',(-25.,210.,-25.));
#1270=DIRECTION('',(0.,1.,0.));
#1271=DIRECTION('',(0.,0.,1.));
#1272=AXIS2_PLACEMENT_3D('',#1269,#1270,#1271);
#1273=SPHERICAL_SURFACE('',#1272,10.);
#1274=ORIENTED_EDGE('',*,*,#1102,.F.);
#1275=ORIENTED_EDGE('',*,*,#467,.F.);
#1276=CARTESIAN_POINT('',(-25.,210.,-25.));
#1277=DIRECTION('',(0.,0.,1.));
#1278=DIRECTION('',(1.,0.,0.));
#1279=AXIS2_PLACEMENT_3D('',#1276,#1277,#1278);
#1280=CIRCLE('',#1279,10.);
#1281=EDGE_CURVE('E44',#1101,#457,#1280,.T.);
#1282=ORIENTED_EDGE('',*,*,#1281,.F.);
#1283=EDGE_LOOP('',(#1274,#1275,#1282));
#1284=FACE_BOUND('',#1283,.T.);
#1285=ADVANCED_FACE('F43',(#1284),#1273,.T.);
#1286=CARTESIAN_POINT('',(25.,210.,-25.));
#1287=DIRECTION('',(0.,1.,0.));
#1288=DIRECTION('',(0.,0.,1.));
#1289=AXIS2_PLACEMENT_3D('',#1286,#1287,#1288);
#1290=SPHERICAL_SURFACE('',#1289,10.);
#1291=ORIENTED_EDGE('',*,*,#417,.F.);
#1292=ORIENTED_EDGE('',*,*,#1030,.F.);
#1293=CARTESIAN_POINT('',(25.,210.,-25.));
#1294=DIRECTION('',(0.,0.,1.));
#1295=DIRECTION('',(1.,0.,0.));
#1296=AXIS2_PLACEMENT_3D('',#1293,#1294,#1295);
#1297=CIRCLE('',#1296,10.);
#1298=EDGE_CURVE('E254',#385,#1022,#1297,.T.);
#1299=ORIENTED_EDGE('',*,*,#1298,.F.);
#1300=EDGE_LOOP('',(#1291,#1292,#1299));
#1301=FACE_BOUND('',#1300,.T.);
#1302=ADVANCED_FACE('F665',(#1301),#1290,.T.);
#1303=CARTESIAN_POINT('',(-25.,210.,0.));
#1304=DIRECTION('',(0.,0.,-1.));
#1305=DIRECTION('',(-1.,0.,0.));
#1306=AXIS2_PLACEMENT_3D('',#1303,#1304,#1305);
#1307=CYLINDRICAL_SURFACE('',#1306,10.);
#1308=ORIENTED_EDGE('',*,*,#1281,.T.);
#1309=ORIENTED_EDGE('',*,*,#519,.F.);
#1310=CARTESIAN_POINT('',(-25.,210.,25.));
#1311=DIRECTION('',(0.,0.,1.));
#1312=DIRECTION('',(1.,0.,0.));
#1313=AXIS2_PLACEMENT_3D('',#1310,#1311,#1312);
#1314=CIRCLE('',#1313,10.);
#1315=EDGE_CURVE('E246',#1054,#512,#1314,.T.);
#1316=ORIENTED_EDGE('',*,*,#1315,.F.);
#1317=ORIENTED_EDGE('',*,*,#1108,.F.);
#1318=EDGE_LOOP('',(#1308,#1309,#1316,#1317));
#1319=FACE_BOUND('',#1318,.T.);
#1320=ADVANCED_FACE('F660',(#1319),#1307,.T.);
#1321=CARTESIAN_POINT('',(25.,210.,0.));
#1322=DIRECTION('',(0.,0.,1.));
#1323=DIRECTION('',(1.,0.,0.));
#1324=AXIS2_PLACEMENT_3D('',#1321,#1322,#1323);
#1325=CYLINDRICAL_SURFACE('',#1324,10.);
#1326=ORIENTED_EDGE('',*,*,#1298,.T.);
#1327=ORIENTED_EDGE('',*,*,#1023,.F.);
#1328=CARTESIAN_POINT('',(25.,210.,25.));
#1329=DIRECTION('',(0.,0.,1.));
#1330=DIRECTION('',(1.,0.,0.));
#1331=AXIS2_PLACEMENT_3D('',#1328,#1329,#1330);
#1332=CIRCLE('',#1331,10.);
#1333=EDGE_CURVE('E239',#331,#1020,#1332,.T.);
#1334=ORIENTED_EDGE('',*,*,#1333,.F.);
#1335=ORIENTED_EDGE('',*,*,#392,.F.);
#1336=EDGE_LOOP('',(#1326,#1327,#1334,#1335));
#1337=FACE_BOUND('',#1336,.T.);
#1338=ADVANCED_FACE('F252',(#1337),#1325,.T.);
#1339=CARTESIAN_POINT('',(-25.,210.,25.));
#1340=DIRECTION('',(0.,1.,0.));
#1341=DIRECTION('',(0.,0.,1.));
#1342=AXIS2_PLACEMENT_3D('',#1339,#1340,#1341);
#1343=SPHERICAL_SURFACE('',#1342,10.);
#1344=ORIENTED_EDGE('',*,*,#1315,.T.);
#1345=ORIENTED_EDGE('',*,*,#544,.F.);
#1346=CARTESIAN_POINT('',(-25.,210.,25.));
#1347=DIRECTION('',(1.,0.,0.));
#1348=DIRECTION('',(0.,0.,-1.));
#1349=AXIS2_PLACEMENT_3D('',#1346,#1347,#1348);
#1350=CIRCLE('',#1349,10.);
#1351=EDGE_CURVE('E240',#1054,#536,#1350,.T.);
#1352=ORIENTED_EDGE('',*,*,#1351,.F.);
#1353=EDGE_LOOP('',(#1344,#1345,#1352));
#1354=FACE_BOUND('',#1353,.T.);
#1355=ADVANCED_FACE('F655',(#1354),#1343,.T.);
#1356=CARTESIAN_POINT('',(25.,210.,25.));
#1357=DIRECTION('',(0.,1.,0.));
#1358=DIRECTION('',(0.,0.,1.));
#1359=AXIS2_PLACEMENT_3D('',#1356,#1357,#1358);
#1360=SPHERICAL_SURFACE('',#1359,10.);
#1361=ORIENTED_EDGE('',*,*,#341,.F.);
#1362=ORIENTED_EDGE('',*,*,#1333,.T.);
#1363=CARTESIAN_POINT('',(25.,210.,25.));
#1364=DIRECTION('',(-1.,0.,0.));
#1365=DIRECTION('',(0.,0.,1.));
#1366=AXIS2_PLACEMENT_3D('',#1363,#1364,#1365);
#1367=CIRCLE('',#1366,10.);
#1368=EDGE_CURVE('E226',#340,#1020,#1367,.T.);
#1369=ORIENTED_EDGE('',*,*,#1368,.F.);
#1370=EDGE_LOOP('',(#1361,#1362,#1369));
#1371=FACE_BOUND('',#1370,.T.);
#1372=ADVANCED_FACE('F245',(#1371),#1360,.T.);
#1373=CARTESIAN_POINT('',(0.,210.,25.));
#1374=DIRECTION('',(-1.,0.,0.));
#1375=DIRECTION('',(0.,0.,1.));
#1376=AXIS2_PLACEMENT_3D('',#1373,#1374,#1375);
#1377=CYLINDRICAL_SURFACE('',#1376,10.);
#1378=ORIENTED_EDGE('',*,*,#1351,.T.);
#1379=ORIENTED_EDGE('',*,*,#561,.F.);
#1380=ORIENTED_EDGE('',*,*,#1368,.T.);
#1381=ORIENTED_EDGE('',*,*,#1061,.F.);
#1382=EDGE_LOOP('',(#1378,#1379,#1380,#1381));
#1383=FACE_BOUND('',#1382,.T.);
#1384=ADVANCED_FACE('F233',(#1383),#1377,.T.);
#1385=CLOSED_SHELL('',(#58,#320,#352,#398,#429,#446,#479,#525,#550,#567,#599,#623,#648,#673,
#698,#722,#747,#772,#797,#821,#846,#871,#896,#920,#945,#963,#987,#1042,#1066,#1114,#1126,#1138,
#1145,#1152,#1172,#1181,#1201,#1210,#1230,#1239,#1259,#1268,#1285,#1302,#1320,#1338,#1355,#1372,#1384));
#1386=MANIFOLD_SOLID_BREP('B2',#1385);
#1387=ADVANCED_BREP_SHAPE_REPRESENTATION('',(#18,#1386),#14);
#1388=SHAPE_DEFINITION_REPRESENTATION(#9,#1387);
ENDSEC;
END-ISO-10303-21;
